VERSION 5.7 ;
  NOWIREEXTENSIONATPIN ON ;
  DIVIDERCHAR "/" ;
  BUSBITCHARS "[]" ;
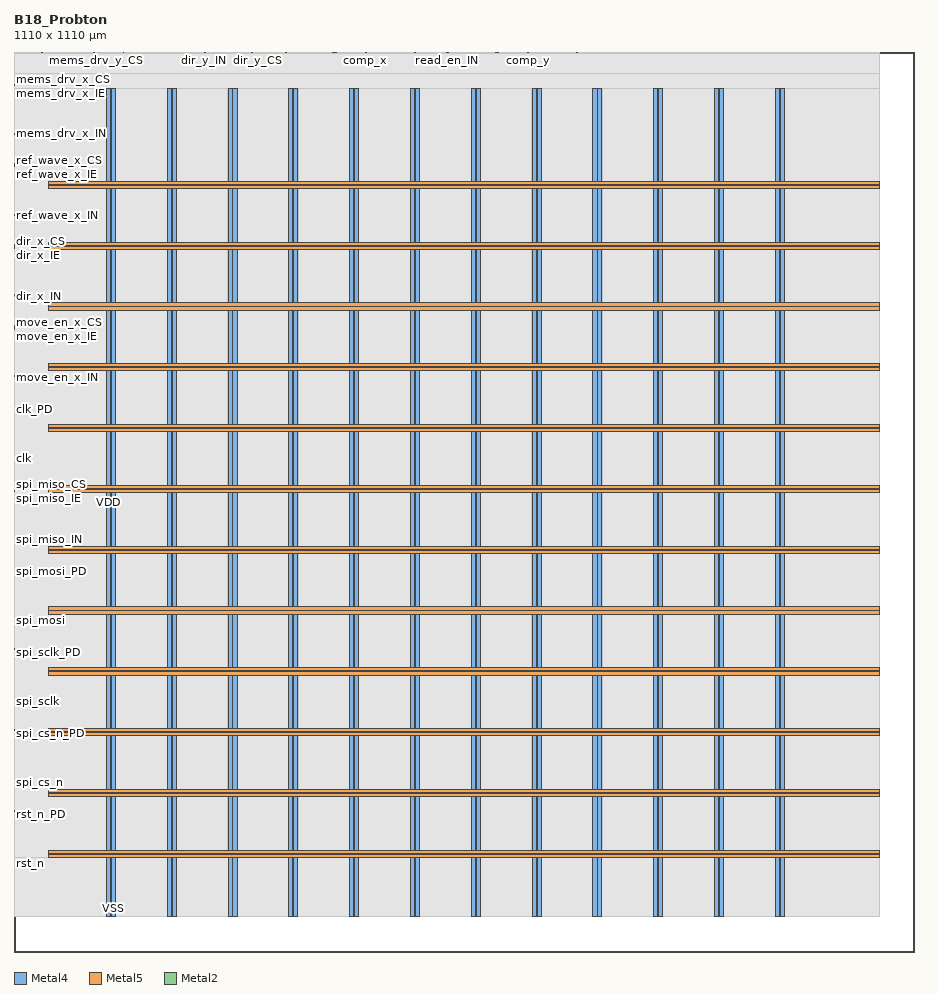
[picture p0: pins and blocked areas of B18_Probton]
MACRO B18_Probton
  CLASS BLOCK ;
  FOREIGN B18_Probton ;
  ORIGIN 0.000 0.000 ;
  SIZE 1110.000 BY 1110.000 ;
  PIN VDD
    DIRECTION INOUT ;
    USE POWER ;
    PORT
      LAYER Metal4 ;
        RECT 114.060 44.220 119.060 1065.140 ;
    END
    PORT
      LAYER Metal4 ;
        RECT 189.060 44.220 194.060 1065.140 ;
    END
    PORT
      LAYER Metal4 ;
        RECT 264.060 44.220 269.060 1065.140 ;
    END
    PORT
      LAYER Metal4 ;
        RECT 339.060 44.220 344.060 1065.140 ;
    END
    PORT
      LAYER Metal4 ;
        RECT 414.060 44.220 419.060 1065.140 ;
    END
    PORT
      LAYER Metal4 ;
        RECT 489.060 44.220 494.060 1065.140 ;
    END
    PORT
      LAYER Metal4 ;
        RECT 564.060 44.220 569.060 1065.140 ;
    END
    PORT
      LAYER Metal4 ;
        RECT 639.060 44.220 644.060 1065.140 ;
    END
    PORT
      LAYER Metal4 ;
        RECT 714.060 44.220 719.060 1065.140 ;
    END
    PORT
      LAYER Metal4 ;
        RECT 789.060 44.220 794.060 1065.140 ;
    END
    PORT
      LAYER Metal4 ;
        RECT 864.060 44.220 869.060 1065.140 ;
    END
    PORT
      LAYER Metal4 ;
        RECT 939.060 44.220 944.060 1065.140 ;
    END
    PORT
      LAYER Metal5 ;
        RECT 42.540 116.570 1067.380 120.570 ;
    END
    PORT
      LAYER Metal5 ;
        RECT 42.540 191.570 1067.380 195.570 ;
    END
    PORT
      LAYER Metal5 ;
        RECT 42.540 266.570 1067.380 270.570 ;
    END
    PORT
      LAYER Metal5 ;
        RECT 42.540 341.570 1067.380 345.570 ;
    END
    PORT
      LAYER Metal5 ;
        RECT 42.540 416.570 1067.380 420.570 ;
    END
    PORT
      LAYER Metal5 ;
        RECT 42.540 491.570 1067.380 495.570 ;
    END
    PORT
      LAYER Metal5 ;
        RECT 42.540 566.570 1067.380 570.570 ;
    END
    PORT
      LAYER Metal5 ;
        RECT 42.540 641.570 1067.380 645.570 ;
    END
    PORT
      LAYER Metal5 ;
        RECT 42.540 716.570 1067.380 720.570 ;
    END
    PORT
      LAYER Metal5 ;
        RECT 42.540 791.570 1067.380 795.570 ;
    END
    PORT
      LAYER Metal5 ;
        RECT 42.540 866.570 1067.380 870.570 ;
    END
    PORT
      LAYER Metal5 ;
        RECT 42.540 941.570 1067.380 945.570 ;
    END
  END VDD
  PIN VSS
    DIRECTION INOUT ;
    USE GROUND ;
    PORT
      LAYER Metal4 ;
        RECT 120.060 44.220 125.060 1065.140 ;
    END
    PORT
      LAYER Metal4 ;
        RECT 195.060 44.220 200.060 1065.140 ;
    END
    PORT
      LAYER Metal4 ;
        RECT 270.060 44.220 275.060 1065.140 ;
    END
    PORT
      LAYER Metal4 ;
        RECT 345.060 44.220 350.060 1065.140 ;
    END
    PORT
      LAYER Metal4 ;
        RECT 420.060 44.220 425.060 1065.140 ;
    END
    PORT
      LAYER Metal4 ;
        RECT 495.060 44.220 500.060 1065.140 ;
    END
    PORT
      LAYER Metal4 ;
        RECT 570.060 44.220 575.060 1065.140 ;
    END
    PORT
      LAYER Metal4 ;
        RECT 645.060 44.220 650.060 1065.140 ;
    END
    PORT
      LAYER Metal4 ;
        RECT 720.060 44.220 725.060 1065.140 ;
    END
    PORT
      LAYER Metal4 ;
        RECT 795.060 44.220 800.060 1065.140 ;
    END
    PORT
      LAYER Metal4 ;
        RECT 870.060 44.220 875.060 1065.140 ;
    END
    PORT
      LAYER Metal4 ;
        RECT 945.060 44.220 950.060 1065.140 ;
    END
    PORT
      LAYER Metal5 ;
        RECT 42.540 121.570 1067.380 125.570 ;
    END
    PORT
      LAYER Metal5 ;
        RECT 42.540 196.570 1067.380 200.570 ;
    END
    PORT
      LAYER Metal5 ;
        RECT 42.540 271.570 1067.380 275.570 ;
    END
    PORT
      LAYER Metal5 ;
        RECT 42.540 346.570 1067.380 350.570 ;
    END
    PORT
      LAYER Metal5 ;
        RECT 42.540 421.570 1067.380 425.570 ;
    END
    PORT
      LAYER Metal5 ;
        RECT 42.540 496.570 1067.380 500.570 ;
    END
    PORT
      LAYER Metal5 ;
        RECT 42.540 571.570 1067.380 575.570 ;
    END
    PORT
      LAYER Metal5 ;
        RECT 42.540 646.570 1067.380 650.570 ;
    END
    PORT
      LAYER Metal5 ;
        RECT 42.540 721.570 1067.380 725.570 ;
    END
    PORT
      LAYER Metal5 ;
        RECT 42.540 796.570 1067.380 800.570 ;
    END
    PORT
      LAYER Metal5 ;
        RECT 42.540 871.570 1067.380 875.570 ;
    END
    PORT
      LAYER Metal5 ;
        RECT 42.540 946.570 1067.380 950.570 ;
    END
  END VSS
  PIN clk
    DIRECTION INPUT ;
    USE SIGNAL ;
    ANTENNAGATEAREA 4.738000 ;
    ANTENNADIFFAREA 0.410400 ;
    PORT
      LAYER Metal2 ;
        RECT 0.000 608.760 1.000 609.140 ;
    END
  END clk
  PIN clk_PD
    DIRECTION OUTPUT ;
    USE SIGNAL ;
    ANTENNADIFFAREA 0.360800 ;
    PORT
      LAYER Metal2 ;
        RECT 0.000 669.290 1.000 669.670 ;
    END
  END clk_PD
  PIN clk_PU
    DIRECTION OUTPUT ;
    USE SIGNAL ;
    ANTENNADIFFAREA 0.360800 ;
    PORT
      LAYER Metal2 ;
        RECT 0.000 673.655 1.000 674.035 ;
    END
  END clk_PU
  PIN comp_x
    DIRECTION INPUT ;
    USE SIGNAL ;
    ANTENNAGATEAREA 0.741000 ;
    ANTENNADIFFAREA 0.410400 ;
    PORT
      LAYER Metal2 ;
        RECT 433.760 1109.000 434.140 1110.000 ;
    END
  END comp_x
  PIN comp_x_PD
    DIRECTION OUTPUT ;
    USE SIGNAL ;
    ANTENNADIFFAREA 0.360800 ;
    PORT
      LAYER Metal2 ;
        RECT 494.290 1109.000 494.670 1110.000 ;
    END
  END comp_x_PD
  PIN comp_x_PU
    DIRECTION OUTPUT ;
    USE SIGNAL ;
    ANTENNADIFFAREA 0.360800 ;
    PORT
      LAYER Metal2 ;
        RECT 498.655 1109.000 499.035 1110.000 ;
    END
  END comp_x_PU
  PIN comp_y
    DIRECTION INPUT ;
    USE SIGNAL ;
    ANTENNAGATEAREA 0.498500 ;
    ANTENNADIFFAREA 0.410400 ;
    PORT
      LAYER Metal2 ;
        RECT 633.760 1109.000 634.140 1110.000 ;
    END
  END comp_y
  PIN comp_y_PD
    DIRECTION OUTPUT ;
    USE SIGNAL ;
    ANTENNADIFFAREA 0.360800 ;
    PORT
      LAYER Metal2 ;
        RECT 694.290 1109.000 694.670 1110.000 ;
    END
  END comp_y_PD
  PIN comp_y_PU
    DIRECTION OUTPUT ;
    USE SIGNAL ;
    ANTENNADIFFAREA 0.360800 ;
    PORT
      LAYER Metal2 ;
        RECT 698.655 1109.000 699.035 1110.000 ;
    END
  END comp_y_PU
  PIN dir_x_CS
    DIRECTION OUTPUT ;
    USE SIGNAL ;
    ANTENNADIFFAREA 0.360800 ;
    PORT
      LAYER Metal2 ;
        RECT 0.000 876.260 1.000 876.640 ;
    END
  END dir_x_CS
  PIN dir_x_IE
    DIRECTION OUTPUT ;
    USE SIGNAL ;
    ANTENNADIFFAREA 0.360800 ;
    PORT
      LAYER Metal2 ;
        RECT 0.000 868.235 1.000 868.615 ;
    END
  END dir_x_IE
  PIN dir_x_IN
    DIRECTION INPUT ;
    USE SIGNAL ;
    PORT
      LAYER Metal2 ;
        RECT 0.000 808.760 1.000 809.140 ;
    END
  END dir_x_IN
  PIN dir_x_OE
    DIRECTION OUTPUT ;
    USE SIGNAL ;
    ANTENNADIFFAREA 0.536800 ;
    PORT
      LAYER Metal2 ;
        RECT 0.000 809.490 1.000 809.870 ;
    END
  END dir_x_OE
  PIN dir_x_OUT
    DIRECTION OUTPUT ;
    USE SIGNAL ;
    ANTENNADIFFAREA 1.182800 ;
    PORT
      LAYER Metal2 ;
        RECT 0.000 810.220 1.000 810.600 ;
    END
  END dir_x_OUT
  PIN dir_x_PD
    DIRECTION OUTPUT ;
    USE SIGNAL ;
    ANTENNADIFFAREA 0.360800 ;
    PORT
      LAYER Metal2 ;
        RECT 0.000 869.290 1.000 869.670 ;
    END
  END dir_x_PD
  PIN dir_x_PDRV0
    DIRECTION OUTPUT ;
    USE SIGNAL ;
    ANTENNADIFFAREA 0.536800 ;
    PORT
      LAYER Metal2 ;
        RECT 0.000 872.510 1.000 872.890 ;
    END
  END dir_x_PDRV0
  PIN dir_x_PDRV1
    DIRECTION OUTPUT ;
    USE SIGNAL ;
    ANTENNADIFFAREA 0.360800 ;
    PORT
      LAYER Metal2 ;
        RECT 0.000 871.800 1.000 872.180 ;
    END
  END dir_x_PDRV1
  PIN dir_x_PU
    DIRECTION OUTPUT ;
    USE SIGNAL ;
    ANTENNADIFFAREA 0.360800 ;
    PORT
      LAYER Metal2 ;
        RECT 0.000 873.655 1.000 874.035 ;
    END
  END dir_x_PU
  PIN dir_x_SL
    DIRECTION OUTPUT ;
    USE SIGNAL ;
    ANTENNADIFFAREA 0.360800 ;
    PORT
      LAYER Metal2 ;
        RECT 0.000 810.950 1.000 811.330 ;
    END
  END dir_x_SL
  PIN dir_y_CS
    DIRECTION OUTPUT ;
    USE SIGNAL ;
    ANTENNADIFFAREA 0.360800 ;
    PORT
      LAYER Metal2 ;
        RECT 301.260 1109.000 301.640 1110.000 ;
    END
  END dir_y_CS
  PIN dir_y_IE
    DIRECTION OUTPUT ;
    USE SIGNAL ;
    ANTENNADIFFAREA 0.360800 ;
    PORT
      LAYER Metal2 ;
        RECT 293.235 1109.000 293.615 1110.000 ;
    END
  END dir_y_IE
  PIN dir_y_IN
    DIRECTION INPUT ;
    USE SIGNAL ;
    PORT
      LAYER Metal2 ;
        RECT 233.760 1109.000 234.140 1110.000 ;
    END
  END dir_y_IN
  PIN dir_y_OE
    DIRECTION OUTPUT ;
    USE SIGNAL ;
    ANTENNADIFFAREA 0.536800 ;
    PORT
      LAYER Metal2 ;
        RECT 234.490 1109.000 234.870 1110.000 ;
    END
  END dir_y_OE
  PIN dir_y_OUT
    DIRECTION OUTPUT ;
    USE SIGNAL ;
    ANTENNADIFFAREA 1.182800 ;
    PORT
      LAYER Metal2 ;
        RECT 235.220 1109.000 235.600 1110.000 ;
    END
  END dir_y_OUT
  PIN dir_y_PD
    DIRECTION OUTPUT ;
    USE SIGNAL ;
    ANTENNADIFFAREA 0.360800 ;
    PORT
      LAYER Metal2 ;
        RECT 294.290 1109.000 294.670 1110.000 ;
    END
  END dir_y_PD
  PIN dir_y_PDRV0
    DIRECTION OUTPUT ;
    USE SIGNAL ;
    ANTENNADIFFAREA 0.536800 ;
    PORT
      LAYER Metal2 ;
        RECT 297.510 1109.000 297.890 1110.000 ;
    END
  END dir_y_PDRV0
  PIN dir_y_PDRV1
    DIRECTION OUTPUT ;
    USE SIGNAL ;
    ANTENNADIFFAREA 0.360800 ;
    PORT
      LAYER Metal2 ;
        RECT 296.800 1109.000 297.180 1110.000 ;
    END
  END dir_y_PDRV1
  PIN dir_y_PU
    DIRECTION OUTPUT ;
    USE SIGNAL ;
    ANTENNADIFFAREA 0.360800 ;
    PORT
      LAYER Metal2 ;
        RECT 298.655 1109.000 299.035 1110.000 ;
    END
  END dir_y_PU
  PIN dir_y_SL
    DIRECTION OUTPUT ;
    USE SIGNAL ;
    ANTENNADIFFAREA 0.360800 ;
    PORT
      LAYER Metal2 ;
        RECT 235.950 1109.000 236.330 1110.000 ;
    END
  END dir_y_SL
  PIN mems_drv_x_CS
    DIRECTION OUTPUT ;
    USE SIGNAL ;
    ANTENNADIFFAREA 0.360800 ;
    PORT
      LAYER Metal2 ;
        RECT 0.000 1076.260 1.000 1076.640 ;
    END
  END mems_drv_x_CS
  PIN mems_drv_x_IE
    DIRECTION OUTPUT ;
    USE SIGNAL ;
    ANTENNADIFFAREA 0.360800 ;
    PORT
      LAYER Metal2 ;
        RECT 0.000 1068.235 1.000 1068.615 ;
    END
  END mems_drv_x_IE
  PIN mems_drv_x_IN
    DIRECTION INPUT ;
    USE SIGNAL ;
    PORT
      LAYER Metal2 ;
        RECT 0.000 1008.760 1.000 1009.140 ;
    END
  END mems_drv_x_IN
  PIN mems_drv_x_OE
    DIRECTION OUTPUT ;
    USE SIGNAL ;
    ANTENNADIFFAREA 0.536800 ;
    PORT
      LAYER Metal2 ;
        RECT 0.000 1009.490 1.000 1009.870 ;
    END
  END mems_drv_x_OE
  PIN mems_drv_x_OUT
    DIRECTION OUTPUT ;
    USE SIGNAL ;
    ANTENNADIFFAREA 1.182800 ;
    PORT
      LAYER Metal2 ;
        RECT 0.000 1010.220 1.000 1010.600 ;
    END
  END mems_drv_x_OUT
  PIN mems_drv_x_PD
    DIRECTION OUTPUT ;
    USE SIGNAL ;
    ANTENNADIFFAREA 0.360800 ;
    PORT
      LAYER Metal2 ;
        RECT 0.000 1069.290 1.000 1069.670 ;
    END
  END mems_drv_x_PD
  PIN mems_drv_x_PDRV0
    DIRECTION OUTPUT ;
    USE SIGNAL ;
    ANTENNADIFFAREA 0.536800 ;
    PORT
      LAYER Metal2 ;
        RECT 0.000 1072.510 1.000 1072.890 ;
    END
  END mems_drv_x_PDRV0
  PIN mems_drv_x_PDRV1
    DIRECTION OUTPUT ;
    USE SIGNAL ;
    ANTENNADIFFAREA 0.360800 ;
    PORT
      LAYER Metal2 ;
        RECT 0.000 1071.800 1.000 1072.180 ;
    END
  END mems_drv_x_PDRV1
  PIN mems_drv_x_PU
    DIRECTION OUTPUT ;
    USE SIGNAL ;
    ANTENNADIFFAREA 0.360800 ;
    PORT
      LAYER Metal2 ;
        RECT 0.000 1073.655 1.000 1074.035 ;
    END
  END mems_drv_x_PU
  PIN mems_drv_x_SL
    DIRECTION OUTPUT ;
    USE SIGNAL ;
    ANTENNADIFFAREA 0.360800 ;
    PORT
      LAYER Metal2 ;
        RECT 0.000 1010.950 1.000 1011.330 ;
    END
  END mems_drv_x_SL
  PIN mems_drv_y_CS
    DIRECTION OUTPUT ;
    USE SIGNAL ;
    ANTENNADIFFAREA 0.360800 ;
    PORT
      LAYER Metal2 ;
        RECT 101.260 1109.000 101.640 1110.000 ;
    END
  END mems_drv_y_CS
  PIN mems_drv_y_IE
    DIRECTION OUTPUT ;
    USE SIGNAL ;
    ANTENNADIFFAREA 0.360800 ;
    PORT
      LAYER Metal2 ;
        RECT 93.235 1109.000 93.615 1110.000 ;
    END
  END mems_drv_y_IE
  PIN mems_drv_y_IN
    DIRECTION INPUT ;
    USE SIGNAL ;
    PORT
      LAYER Metal2 ;
        RECT 33.760 1109.000 34.140 1110.000 ;
    END
  END mems_drv_y_IN
  PIN mems_drv_y_OE
    DIRECTION OUTPUT ;
    USE SIGNAL ;
    ANTENNADIFFAREA 0.536800 ;
    PORT
      LAYER Metal2 ;
        RECT 34.490 1109.000 34.870 1110.000 ;
    END
  END mems_drv_y_OE
  PIN mems_drv_y_OUT
    DIRECTION OUTPUT ;
    USE SIGNAL ;
    ANTENNADIFFAREA 1.182800 ;
    PORT
      LAYER Metal2 ;
        RECT 35.220 1109.000 35.600 1110.000 ;
    END
  END mems_drv_y_OUT
  PIN mems_drv_y_PD
    DIRECTION OUTPUT ;
    USE SIGNAL ;
    ANTENNADIFFAREA 0.360800 ;
    PORT
      LAYER Metal2 ;
        RECT 94.290 1109.000 94.670 1110.000 ;
    END
  END mems_drv_y_PD
  PIN mems_drv_y_PDRV0
    DIRECTION OUTPUT ;
    USE SIGNAL ;
    ANTENNADIFFAREA 0.536800 ;
    PORT
      LAYER Metal2 ;
        RECT 97.510 1109.000 97.890 1110.000 ;
    END
  END mems_drv_y_PDRV0
  PIN mems_drv_y_PDRV1
    DIRECTION OUTPUT ;
    USE SIGNAL ;
    ANTENNADIFFAREA 0.360800 ;
    PORT
      LAYER Metal2 ;
        RECT 96.800 1109.000 97.180 1110.000 ;
    END
  END mems_drv_y_PDRV1
  PIN mems_drv_y_PU
    DIRECTION OUTPUT ;
    USE SIGNAL ;
    ANTENNADIFFAREA 0.360800 ;
    PORT
      LAYER Metal2 ;
        RECT 98.655 1109.000 99.035 1110.000 ;
    END
  END mems_drv_y_PU
  PIN mems_drv_y_SL
    DIRECTION OUTPUT ;
    USE SIGNAL ;
    ANTENNADIFFAREA 0.360800 ;
    PORT
      LAYER Metal2 ;
        RECT 35.950 1109.000 36.330 1110.000 ;
    END
  END mems_drv_y_SL
  PIN move_en_x_CS
    DIRECTION OUTPUT ;
    USE SIGNAL ;
    ANTENNADIFFAREA 0.360800 ;
    PORT
      LAYER Metal2 ;
        RECT 0.000 776.260 1.000 776.640 ;
    END
  END move_en_x_CS
  PIN move_en_x_IE
    DIRECTION OUTPUT ;
    USE SIGNAL ;
    ANTENNADIFFAREA 0.360800 ;
    PORT
      LAYER Metal2 ;
        RECT 0.000 768.235 1.000 768.615 ;
    END
  END move_en_x_IE
  PIN move_en_x_IN
    DIRECTION INPUT ;
    USE SIGNAL ;
    PORT
      LAYER Metal2 ;
        RECT 0.000 708.760 1.000 709.140 ;
    END
  END move_en_x_IN
  PIN move_en_x_OE
    DIRECTION OUTPUT ;
    USE SIGNAL ;
    ANTENNADIFFAREA 0.536800 ;
    PORT
      LAYER Metal2 ;
        RECT 0.000 709.490 1.000 709.870 ;
    END
  END move_en_x_OE
  PIN move_en_x_OUT
    DIRECTION OUTPUT ;
    USE SIGNAL ;
    ANTENNADIFFAREA 1.182800 ;
    PORT
      LAYER Metal2 ;
        RECT 0.000 710.220 1.000 710.600 ;
    END
  END move_en_x_OUT
  PIN move_en_x_PD
    DIRECTION OUTPUT ;
    USE SIGNAL ;
    ANTENNADIFFAREA 0.360800 ;
    PORT
      LAYER Metal2 ;
        RECT 0.000 769.290 1.000 769.670 ;
    END
  END move_en_x_PD
  PIN move_en_x_PDRV0
    DIRECTION OUTPUT ;
    USE SIGNAL ;
    ANTENNADIFFAREA 0.536800 ;
    PORT
      LAYER Metal2 ;
        RECT 0.000 772.510 1.000 772.890 ;
    END
  END move_en_x_PDRV0
  PIN move_en_x_PDRV1
    DIRECTION OUTPUT ;
    USE SIGNAL ;
    ANTENNADIFFAREA 0.360800 ;
    PORT
      LAYER Metal2 ;
        RECT 0.000 771.800 1.000 772.180 ;
    END
  END move_en_x_PDRV1
  PIN move_en_x_PU
    DIRECTION OUTPUT ;
    USE SIGNAL ;
    ANTENNADIFFAREA 0.360800 ;
    PORT
      LAYER Metal2 ;
        RECT 0.000 773.655 1.000 774.035 ;
    END
  END move_en_x_PU
  PIN move_en_x_SL
    DIRECTION OUTPUT ;
    USE SIGNAL ;
    ANTENNADIFFAREA 0.360800 ;
    PORT
      LAYER Metal2 ;
        RECT 0.000 710.950 1.000 711.330 ;
    END
  END move_en_x_SL
  PIN move_en_y_CS
    DIRECTION OUTPUT ;
    USE SIGNAL ;
    ANTENNADIFFAREA 0.360800 ;
    PORT
      LAYER Metal2 ;
        RECT 401.260 1109.000 401.640 1110.000 ;
    END
  END move_en_y_CS
  PIN move_en_y_IE
    DIRECTION OUTPUT ;
    USE SIGNAL ;
    ANTENNADIFFAREA 0.360800 ;
    PORT
      LAYER Metal2 ;
        RECT 393.235 1109.000 393.615 1110.000 ;
    END
  END move_en_y_IE
  PIN move_en_y_IN
    DIRECTION INPUT ;
    USE SIGNAL ;
    PORT
      LAYER Metal2 ;
        RECT 333.760 1109.000 334.140 1110.000 ;
    END
  END move_en_y_IN
  PIN move_en_y_OE
    DIRECTION OUTPUT ;
    USE SIGNAL ;
    ANTENNADIFFAREA 0.536800 ;
    PORT
      LAYER Metal2 ;
        RECT 334.490 1109.000 334.870 1110.000 ;
    END
  END move_en_y_OE
  PIN move_en_y_OUT
    DIRECTION OUTPUT ;
    USE SIGNAL ;
    ANTENNADIFFAREA 1.182800 ;
    PORT
      LAYER Metal2 ;
        RECT 335.220 1109.000 335.600 1110.000 ;
    END
  END move_en_y_OUT
  PIN move_en_y_PD
    DIRECTION OUTPUT ;
    USE SIGNAL ;
    ANTENNADIFFAREA 0.360800 ;
    PORT
      LAYER Metal2 ;
        RECT 394.290 1109.000 394.670 1110.000 ;
    END
  END move_en_y_PD
  PIN move_en_y_PDRV0
    DIRECTION OUTPUT ;
    USE SIGNAL ;
    ANTENNADIFFAREA 0.536800 ;
    PORT
      LAYER Metal2 ;
        RECT 397.510 1109.000 397.890 1110.000 ;
    END
  END move_en_y_PDRV0
  PIN move_en_y_PDRV1
    DIRECTION OUTPUT ;
    USE SIGNAL ;
    ANTENNADIFFAREA 0.360800 ;
    PORT
      LAYER Metal2 ;
        RECT 396.800 1109.000 397.180 1110.000 ;
    END
  END move_en_y_PDRV1
  PIN move_en_y_PU
    DIRECTION OUTPUT ;
    USE SIGNAL ;
    ANTENNADIFFAREA 0.360800 ;
    PORT
      LAYER Metal2 ;
        RECT 398.655 1109.000 399.035 1110.000 ;
    END
  END move_en_y_PU
  PIN move_en_y_SL
    DIRECTION OUTPUT ;
    USE SIGNAL ;
    ANTENNADIFFAREA 0.360800 ;
    PORT
      LAYER Metal2 ;
        RECT 335.950 1109.000 336.330 1110.000 ;
    END
  END move_en_y_SL
  PIN read_en_CS
    DIRECTION OUTPUT ;
    USE SIGNAL ;
    ANTENNADIFFAREA 0.360800 ;
    PORT
      LAYER Metal2 ;
        RECT 601.260 1109.000 601.640 1110.000 ;
    END
  END read_en_CS
  PIN read_en_IE
    DIRECTION OUTPUT ;
    USE SIGNAL ;
    ANTENNADIFFAREA 0.360800 ;
    PORT
      LAYER Metal2 ;
        RECT 593.235 1109.000 593.615 1110.000 ;
    END
  END read_en_IE
  PIN read_en_IN
    DIRECTION INPUT ;
    USE SIGNAL ;
    PORT
      LAYER Metal2 ;
        RECT 533.760 1109.000 534.140 1110.000 ;
    END
  END read_en_IN
  PIN read_en_OE
    DIRECTION OUTPUT ;
    USE SIGNAL ;
    ANTENNADIFFAREA 0.536800 ;
    PORT
      LAYER Metal2 ;
        RECT 534.490 1109.000 534.870 1110.000 ;
    END
  END read_en_OE
  PIN read_en_OUT
    DIRECTION OUTPUT ;
    USE SIGNAL ;
    ANTENNADIFFAREA 1.182800 ;
    PORT
      LAYER Metal2 ;
        RECT 535.220 1109.000 535.600 1110.000 ;
    END
  END read_en_OUT
  PIN read_en_PD
    DIRECTION OUTPUT ;
    USE SIGNAL ;
    ANTENNADIFFAREA 0.360800 ;
    PORT
      LAYER Metal2 ;
        RECT 594.290 1109.000 594.670 1110.000 ;
    END
  END read_en_PD
  PIN read_en_PDRV0
    DIRECTION OUTPUT ;
    USE SIGNAL ;
    ANTENNADIFFAREA 0.536800 ;
    PORT
      LAYER Metal2 ;
        RECT 597.510 1109.000 597.890 1110.000 ;
    END
  END read_en_PDRV0
  PIN read_en_PDRV1
    DIRECTION OUTPUT ;
    USE SIGNAL ;
    ANTENNADIFFAREA 0.360800 ;
    PORT
      LAYER Metal2 ;
        RECT 596.800 1109.000 597.180 1110.000 ;
    END
  END read_en_PDRV1
  PIN read_en_PU
    DIRECTION OUTPUT ;
    USE SIGNAL ;
    ANTENNADIFFAREA 0.360800 ;
    PORT
      LAYER Metal2 ;
        RECT 598.655 1109.000 599.035 1110.000 ;
    END
  END read_en_PU
  PIN read_en_SL
    DIRECTION OUTPUT ;
    USE SIGNAL ;
    ANTENNADIFFAREA 0.360800 ;
    PORT
      LAYER Metal2 ;
        RECT 535.950 1109.000 536.330 1110.000 ;
    END
  END read_en_SL
  PIN ref_wave_x_CS
    DIRECTION OUTPUT ;
    USE SIGNAL ;
    ANTENNADIFFAREA 0.360800 ;
    PORT
      LAYER Metal2 ;
        RECT 0.000 976.260 1.000 976.640 ;
    END
  END ref_wave_x_CS
  PIN ref_wave_x_IE
    DIRECTION OUTPUT ;
    USE SIGNAL ;
    ANTENNADIFFAREA 0.360800 ;
    PORT
      LAYER Metal2 ;
        RECT 0.000 968.235 1.000 968.615 ;
    END
  END ref_wave_x_IE
  PIN ref_wave_x_IN
    DIRECTION INPUT ;
    USE SIGNAL ;
    PORT
      LAYER Metal2 ;
        RECT 0.000 908.760 1.000 909.140 ;
    END
  END ref_wave_x_IN
  PIN ref_wave_x_OE
    DIRECTION OUTPUT ;
    USE SIGNAL ;
    ANTENNADIFFAREA 0.536800 ;
    PORT
      LAYER Metal2 ;
        RECT 0.000 909.490 1.000 909.870 ;
    END
  END ref_wave_x_OE
  PIN ref_wave_x_OUT
    DIRECTION OUTPUT ;
    USE SIGNAL ;
    ANTENNADIFFAREA 1.182800 ;
    PORT
      LAYER Metal2 ;
        RECT 0.000 910.220 1.000 910.600 ;
    END
  END ref_wave_x_OUT
  PIN ref_wave_x_PD
    DIRECTION OUTPUT ;
    USE SIGNAL ;
    ANTENNADIFFAREA 0.360800 ;
    PORT
      LAYER Metal2 ;
        RECT 0.000 969.290 1.000 969.670 ;
    END
  END ref_wave_x_PD
  PIN ref_wave_x_PDRV0
    DIRECTION OUTPUT ;
    USE SIGNAL ;
    ANTENNADIFFAREA 0.536800 ;
    PORT
      LAYER Metal2 ;
        RECT 0.000 972.510 1.000 972.890 ;
    END
  END ref_wave_x_PDRV0
  PIN ref_wave_x_PDRV1
    DIRECTION OUTPUT ;
    USE SIGNAL ;
    ANTENNADIFFAREA 0.360800 ;
    PORT
      LAYER Metal2 ;
        RECT 0.000 971.800 1.000 972.180 ;
    END
  END ref_wave_x_PDRV1
  PIN ref_wave_x_PU
    DIRECTION OUTPUT ;
    USE SIGNAL ;
    ANTENNADIFFAREA 0.360800 ;
    PORT
      LAYER Metal2 ;
        RECT 0.000 973.655 1.000 974.035 ;
    END
  END ref_wave_x_PU
  PIN ref_wave_x_SL
    DIRECTION OUTPUT ;
    USE SIGNAL ;
    ANTENNADIFFAREA 0.360800 ;
    PORT
      LAYER Metal2 ;
        RECT 0.000 910.950 1.000 911.330 ;
    END
  END ref_wave_x_SL
  PIN ref_wave_y_CS
    DIRECTION OUTPUT ;
    USE SIGNAL ;
    ANTENNADIFFAREA 0.360800 ;
    PORT
      LAYER Metal2 ;
        RECT 201.260 1109.000 201.640 1110.000 ;
    END
  END ref_wave_y_CS
  PIN ref_wave_y_IE
    DIRECTION OUTPUT ;
    USE SIGNAL ;
    ANTENNADIFFAREA 0.360800 ;
    PORT
      LAYER Metal2 ;
        RECT 193.235 1109.000 193.615 1110.000 ;
    END
  END ref_wave_y_IE
  PIN ref_wave_y_IN
    DIRECTION INPUT ;
    USE SIGNAL ;
    PORT
      LAYER Metal2 ;
        RECT 133.760 1109.000 134.140 1110.000 ;
    END
  END ref_wave_y_IN
  PIN ref_wave_y_OE
    DIRECTION OUTPUT ;
    USE SIGNAL ;
    ANTENNADIFFAREA 0.536800 ;
    PORT
      LAYER Metal2 ;
        RECT 134.490 1109.000 134.870 1110.000 ;
    END
  END ref_wave_y_OE
  PIN ref_wave_y_OUT
    DIRECTION OUTPUT ;
    USE SIGNAL ;
    ANTENNADIFFAREA 1.182800 ;
    PORT
      LAYER Metal2 ;
        RECT 135.220 1109.000 135.600 1110.000 ;
    END
  END ref_wave_y_OUT
  PIN ref_wave_y_PD
    DIRECTION OUTPUT ;
    USE SIGNAL ;
    ANTENNADIFFAREA 0.360800 ;
    PORT
      LAYER Metal2 ;
        RECT 194.290 1109.000 194.670 1110.000 ;
    END
  END ref_wave_y_PD
  PIN ref_wave_y_PDRV0
    DIRECTION OUTPUT ;
    USE SIGNAL ;
    ANTENNADIFFAREA 0.536800 ;
    PORT
      LAYER Metal2 ;
        RECT 197.510 1109.000 197.890 1110.000 ;
    END
  END ref_wave_y_PDRV0
  PIN ref_wave_y_PDRV1
    DIRECTION OUTPUT ;
    USE SIGNAL ;
    ANTENNADIFFAREA 0.360800 ;
    PORT
      LAYER Metal2 ;
        RECT 196.800 1109.000 197.180 1110.000 ;
    END
  END ref_wave_y_PDRV1
  PIN ref_wave_y_PU
    DIRECTION OUTPUT ;
    USE SIGNAL ;
    ANTENNADIFFAREA 0.360800 ;
    PORT
      LAYER Metal2 ;
        RECT 198.655 1109.000 199.035 1110.000 ;
    END
  END ref_wave_y_PU
  PIN ref_wave_y_SL
    DIRECTION OUTPUT ;
    USE SIGNAL ;
    ANTENNADIFFAREA 0.360800 ;
    PORT
      LAYER Metal2 ;
        RECT 135.950 1109.000 136.330 1110.000 ;
    END
  END ref_wave_y_SL
  PIN rst_n
    DIRECTION INPUT ;
    USE SIGNAL ;
    ANTENNAGATEAREA 1.102000 ;
    ANTENNADIFFAREA 0.410400 ;
    PORT
      LAYER Metal2 ;
        RECT 0.000 108.760 1.000 109.140 ;
    END
  END rst_n
  PIN rst_n_PD
    DIRECTION OUTPUT ;
    USE SIGNAL ;
    ANTENNADIFFAREA 0.360800 ;
    PORT
      LAYER Metal2 ;
        RECT 0.000 169.290 1.000 169.670 ;
    END
  END rst_n_PD
  PIN rst_n_PU
    DIRECTION OUTPUT ;
    USE SIGNAL ;
    ANTENNADIFFAREA 0.536800 ;
    PORT
      LAYER Metal2 ;
        RECT 0.000 173.655 1.000 174.035 ;
    END
  END rst_n_PU
  PIN spi_cs_n
    DIRECTION INPUT ;
    USE SIGNAL ;
    ANTENNAGATEAREA 1.102000 ;
    ANTENNADIFFAREA 0.410400 ;
    PORT
      LAYER Metal2 ;
        RECT 0.000 208.760 1.000 209.140 ;
    END
  END spi_cs_n
  PIN spi_cs_n_PD
    DIRECTION OUTPUT ;
    USE SIGNAL ;
    ANTENNADIFFAREA 0.360800 ;
    PORT
      LAYER Metal2 ;
        RECT 0.000 269.290 1.000 269.670 ;
    END
  END spi_cs_n_PD
  PIN spi_cs_n_PU
    DIRECTION OUTPUT ;
    USE SIGNAL ;
    ANTENNADIFFAREA 0.536800 ;
    PORT
      LAYER Metal2 ;
        RECT 0.000 273.655 1.000 274.035 ;
    END
  END spi_cs_n_PU
  PIN spi_miso_CS
    DIRECTION OUTPUT ;
    USE SIGNAL ;
    ANTENNADIFFAREA 0.360800 ;
    PORT
      LAYER Metal2 ;
        RECT 0.000 576.260 1.000 576.640 ;
    END
  END spi_miso_CS
  PIN spi_miso_IE
    DIRECTION OUTPUT ;
    USE SIGNAL ;
    ANTENNADIFFAREA 0.360800 ;
    PORT
      LAYER Metal2 ;
        RECT 0.000 568.235 1.000 568.615 ;
    END
  END spi_miso_IE
  PIN spi_miso_IN
    DIRECTION INPUT ;
    USE SIGNAL ;
    PORT
      LAYER Metal2 ;
        RECT 0.000 508.760 1.000 509.140 ;
    END
  END spi_miso_IN
  PIN spi_miso_OUT
    DIRECTION OUTPUT ;
    USE SIGNAL ;
    ANTENNADIFFAREA 1.182800 ;
    PORT
      LAYER Metal2 ;
        RECT 0.000 510.220 1.000 510.600 ;
    END
  END spi_miso_OUT
  PIN spi_miso_PD
    DIRECTION OUTPUT ;
    USE SIGNAL ;
    ANTENNADIFFAREA 0.360800 ;
    PORT
      LAYER Metal2 ;
        RECT 0.000 569.290 1.000 569.670 ;
    END
  END spi_miso_PD
  PIN spi_miso_PDRV0
    DIRECTION OUTPUT ;
    USE SIGNAL ;
    ANTENNADIFFAREA 0.536800 ;
    PORT
      LAYER Metal2 ;
        RECT 0.000 572.510 1.000 572.890 ;
    END
  END spi_miso_PDRV0
  PIN spi_miso_PDRV1
    DIRECTION OUTPUT ;
    USE SIGNAL ;
    ANTENNADIFFAREA 0.360800 ;
    PORT
      LAYER Metal2 ;
        RECT 0.000 571.800 1.000 572.180 ;
    END
  END spi_miso_PDRV1
  PIN spi_miso_PU
    DIRECTION OUTPUT ;
    USE SIGNAL ;
    ANTENNADIFFAREA 0.360800 ;
    PORT
      LAYER Metal2 ;
        RECT 0.000 573.655 1.000 574.035 ;
    END
  END spi_miso_PU
  PIN spi_miso_SL
    DIRECTION OUTPUT ;
    USE SIGNAL ;
    ANTENNADIFFAREA 0.536800 ;
    PORT
      LAYER Metal2 ;
        RECT 0.000 510.950 1.000 511.330 ;
    END
  END spi_miso_SL
  PIN spi_miso_oe
    DIRECTION OUTPUT ;
    USE SIGNAL ;
    ANTENNADIFFAREA 1.182800 ;
    PORT
      LAYER Metal2 ;
        RECT 0.000 509.490 1.000 509.870 ;
    END
  END spi_miso_oe
  PIN spi_mosi
    DIRECTION INPUT ;
    USE SIGNAL ;
    ANTENNAGATEAREA 0.498500 ;
    ANTENNADIFFAREA 0.410400 ;
    PORT
      LAYER Metal2 ;
        RECT 0.000 408.760 1.000 409.140 ;
    END
  END spi_mosi
  PIN spi_mosi_PD
    DIRECTION OUTPUT ;
    USE SIGNAL ;
    ANTENNADIFFAREA 0.360800 ;
    PORT
      LAYER Metal2 ;
        RECT 0.000 469.290 1.000 469.670 ;
    END
  END spi_mosi_PD
  PIN spi_mosi_PU
    DIRECTION OUTPUT ;
    USE SIGNAL ;
    ANTENNADIFFAREA 0.360800 ;
    PORT
      LAYER Metal2 ;
        RECT 0.000 473.655 1.000 474.035 ;
    END
  END spi_mosi_PU
  PIN spi_sclk
    DIRECTION INPUT ;
    USE SIGNAL ;
    ANTENNAGATEAREA 0.498500 ;
    ANTENNADIFFAREA 0.410400 ;
    PORT
      LAYER Metal2 ;
        RECT 0.000 308.760 1.000 309.140 ;
    END
  END spi_sclk
  PIN spi_sclk_PD
    DIRECTION OUTPUT ;
    USE SIGNAL ;
    ANTENNADIFFAREA 0.360800 ;
    PORT
      LAYER Metal2 ;
        RECT 0.000 369.290 1.000 369.670 ;
    END
  END spi_sclk_PD
  PIN spi_sclk_PU
    DIRECTION OUTPUT ;
    USE SIGNAL ;
    ANTENNADIFFAREA 0.360800 ;
    PORT
      LAYER Metal2 ;
        RECT 0.000 373.655 1.000 374.035 ;
    END
  END spi_sclk_PU
  OBS
      LAYER Nwell ;
        RECT 99.810 101.490 1010.110 1007.870 ;
      LAYER Metal1 ;
        RECT 100.240 101.620 1009.680 1007.740 ;
      LAYER Metal2 ;
        RECT 0.000 1108.700 33.460 1110.000 ;
        RECT 36.630 1108.700 92.935 1110.000 ;
        RECT 93.915 1108.700 93.990 1110.000 ;
        RECT 94.970 1108.700 96.500 1110.000 ;
        RECT 98.190 1108.700 98.355 1110.000 ;
        RECT 99.335 1108.700 100.960 1110.000 ;
        RECT 101.940 1108.700 133.460 1110.000 ;
        RECT 136.630 1108.700 192.935 1110.000 ;
        RECT 193.915 1108.700 193.990 1110.000 ;
        RECT 194.970 1108.700 196.500 1110.000 ;
        RECT 198.190 1108.700 198.355 1110.000 ;
        RECT 199.335 1108.700 200.960 1110.000 ;
        RECT 201.940 1108.700 233.460 1110.000 ;
        RECT 236.630 1108.700 292.935 1110.000 ;
        RECT 293.915 1108.700 293.990 1110.000 ;
        RECT 294.970 1108.700 296.500 1110.000 ;
        RECT 298.190 1108.700 298.355 1110.000 ;
        RECT 299.335 1108.700 300.960 1110.000 ;
        RECT 301.940 1108.700 333.460 1110.000 ;
        RECT 336.630 1108.700 392.935 1110.000 ;
        RECT 393.915 1108.700 393.990 1110.000 ;
        RECT 394.970 1108.700 396.500 1110.000 ;
        RECT 398.190 1108.700 398.355 1110.000 ;
        RECT 399.335 1108.700 400.960 1110.000 ;
        RECT 401.940 1108.700 433.460 1110.000 ;
        RECT 434.440 1108.700 493.990 1110.000 ;
        RECT 494.970 1108.700 498.355 1110.000 ;
        RECT 499.335 1108.700 533.460 1110.000 ;
        RECT 536.630 1108.700 592.935 1110.000 ;
        RECT 593.915 1108.700 593.990 1110.000 ;
        RECT 594.970 1108.700 596.500 1110.000 ;
        RECT 598.190 1108.700 598.355 1110.000 ;
        RECT 599.335 1108.700 600.960 1110.000 ;
        RECT 601.940 1108.700 633.460 1110.000 ;
        RECT 634.440 1108.700 693.990 1110.000 ;
        RECT 694.970 1108.700 698.355 1110.000 ;
        RECT 699.335 1108.700 1067.380 1110.000 ;
        RECT 0.000 1076.940 1067.380 1108.700 ;
        RECT 1.300 1075.960 1067.380 1076.940 ;
        RECT 0.000 1074.335 1067.380 1075.960 ;
        RECT 1.300 1073.355 1067.380 1074.335 ;
        RECT 0.000 1073.190 1067.380 1073.355 ;
        RECT 1.300 1071.500 1067.380 1073.190 ;
        RECT 0.000 1069.970 1067.380 1071.500 ;
        RECT 1.300 1068.990 1067.380 1069.970 ;
        RECT 0.000 1068.915 1067.380 1068.990 ;
        RECT 1.300 1067.935 1067.380 1068.915 ;
        RECT 0.000 1011.630 1067.380 1067.935 ;
        RECT 1.300 1008.460 1067.380 1011.630 ;
        RECT 0.000 976.940 1067.380 1008.460 ;
        RECT 1.300 975.960 1067.380 976.940 ;
        RECT 0.000 974.335 1067.380 975.960 ;
        RECT 1.300 973.355 1067.380 974.335 ;
        RECT 0.000 973.190 1067.380 973.355 ;
        RECT 1.300 971.500 1067.380 973.190 ;
        RECT 0.000 969.970 1067.380 971.500 ;
        RECT 1.300 968.990 1067.380 969.970 ;
        RECT 0.000 968.915 1067.380 968.990 ;
        RECT 1.300 967.935 1067.380 968.915 ;
        RECT 0.000 911.630 1067.380 967.935 ;
        RECT 1.300 908.460 1067.380 911.630 ;
        RECT 0.000 876.940 1067.380 908.460 ;
        RECT 1.300 875.960 1067.380 876.940 ;
        RECT 0.000 874.335 1067.380 875.960 ;
        RECT 1.300 873.355 1067.380 874.335 ;
        RECT 0.000 873.190 1067.380 873.355 ;
        RECT 1.300 871.500 1067.380 873.190 ;
        RECT 0.000 869.970 1067.380 871.500 ;
        RECT 1.300 868.990 1067.380 869.970 ;
        RECT 0.000 868.915 1067.380 868.990 ;
        RECT 1.300 867.935 1067.380 868.915 ;
        RECT 0.000 811.630 1067.380 867.935 ;
        RECT 1.300 808.460 1067.380 811.630 ;
        RECT 0.000 776.940 1067.380 808.460 ;
        RECT 1.300 775.960 1067.380 776.940 ;
        RECT 0.000 774.335 1067.380 775.960 ;
        RECT 1.300 773.355 1067.380 774.335 ;
        RECT 0.000 773.190 1067.380 773.355 ;
        RECT 1.300 771.500 1067.380 773.190 ;
        RECT 0.000 769.970 1067.380 771.500 ;
        RECT 1.300 768.990 1067.380 769.970 ;
        RECT 0.000 768.915 1067.380 768.990 ;
        RECT 1.300 767.935 1067.380 768.915 ;
        RECT 0.000 711.630 1067.380 767.935 ;
        RECT 1.300 708.460 1067.380 711.630 ;
        RECT 0.000 674.335 1067.380 708.460 ;
        RECT 1.300 673.355 1067.380 674.335 ;
        RECT 0.000 669.970 1067.380 673.355 ;
        RECT 1.300 668.990 1067.380 669.970 ;
        RECT 0.000 609.440 1067.380 668.990 ;
        RECT 1.300 608.460 1067.380 609.440 ;
        RECT 0.000 576.940 1067.380 608.460 ;
        RECT 1.300 575.960 1067.380 576.940 ;
        RECT 0.000 574.335 1067.380 575.960 ;
        RECT 1.300 573.355 1067.380 574.335 ;
        RECT 0.000 573.190 1067.380 573.355 ;
        RECT 1.300 571.500 1067.380 573.190 ;
        RECT 0.000 569.970 1067.380 571.500 ;
        RECT 1.300 568.990 1067.380 569.970 ;
        RECT 0.000 568.915 1067.380 568.990 ;
        RECT 1.300 567.935 1067.380 568.915 ;
        RECT 0.000 511.630 1067.380 567.935 ;
        RECT 1.300 508.460 1067.380 511.630 ;
        RECT 0.000 474.335 1067.380 508.460 ;
        RECT 1.300 473.355 1067.380 474.335 ;
        RECT 0.000 469.970 1067.380 473.355 ;
        RECT 1.300 468.990 1067.380 469.970 ;
        RECT 0.000 409.440 1067.380 468.990 ;
        RECT 1.300 408.460 1067.380 409.440 ;
        RECT 0.000 374.335 1067.380 408.460 ;
        RECT 1.300 373.355 1067.380 374.335 ;
        RECT 0.000 369.970 1067.380 373.355 ;
        RECT 1.300 368.990 1067.380 369.970 ;
        RECT 0.000 309.440 1067.380 368.990 ;
        RECT 1.300 308.460 1067.380 309.440 ;
        RECT 0.000 274.335 1067.380 308.460 ;
        RECT 1.300 273.355 1067.380 274.335 ;
        RECT 0.000 269.970 1067.380 273.355 ;
        RECT 1.300 268.990 1067.380 269.970 ;
        RECT 0.000 209.440 1067.380 268.990 ;
        RECT 1.300 208.460 1067.380 209.440 ;
        RECT 0.000 174.335 1067.380 208.460 ;
        RECT 1.300 173.355 1067.380 174.335 ;
        RECT 0.000 169.970 1067.380 173.355 ;
        RECT 1.300 168.990 1067.380 169.970 ;
        RECT 0.000 109.440 1067.380 168.990 ;
        RECT 1.300 108.460 1067.380 109.440 ;
        RECT 0.000 44.220 1067.380 108.460 ;
      LAYER Metal3 ;
        RECT 0.090 44.220 1067.380 1108.660 ;
      LAYER Metal4 ;
        RECT 0.140 1065.440 1067.110 1084.070 ;
        RECT 0.140 116.830 113.760 1065.440 ;
        RECT 119.360 116.830 119.760 1065.440 ;
        RECT 125.360 116.830 188.760 1065.440 ;
        RECT 194.360 116.830 194.760 1065.440 ;
        RECT 200.360 116.830 263.760 1065.440 ;
        RECT 269.360 116.830 269.760 1065.440 ;
        RECT 275.360 116.830 338.760 1065.440 ;
        RECT 344.360 116.830 344.760 1065.440 ;
        RECT 350.360 116.830 413.760 1065.440 ;
        RECT 419.360 116.830 419.760 1065.440 ;
        RECT 425.360 116.830 488.760 1065.440 ;
        RECT 494.360 116.830 494.760 1065.440 ;
        RECT 500.360 116.830 563.760 1065.440 ;
        RECT 569.360 116.830 569.760 1065.440 ;
        RECT 575.360 116.830 638.760 1065.440 ;
        RECT 644.360 116.830 644.760 1065.440 ;
        RECT 650.360 116.830 713.760 1065.440 ;
        RECT 719.360 116.830 719.760 1065.440 ;
        RECT 725.360 116.830 788.760 1065.440 ;
        RECT 794.360 116.830 794.760 1065.440 ;
        RECT 800.360 116.830 863.760 1065.440 ;
        RECT 869.360 116.830 869.760 1065.440 ;
        RECT 875.360 116.830 938.760 1065.440 ;
        RECT 944.360 116.830 944.760 1065.440 ;
        RECT 950.360 116.830 1067.110 1065.440 ;
  END
END B18_Probton
END LIBRARY

